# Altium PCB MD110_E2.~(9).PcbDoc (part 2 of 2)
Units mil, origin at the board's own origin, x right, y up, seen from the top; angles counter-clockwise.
Board outline 2320.51 x 1908 mil, 4 copper layers (Top Layer, Signal Layer 1, Signal Layer 2, Bottom Layer), stack 61.2 mil thick; 89 components, 32 nets, 187 pads, 40 vias.
Unrouted connection lines stored in the file: 7.

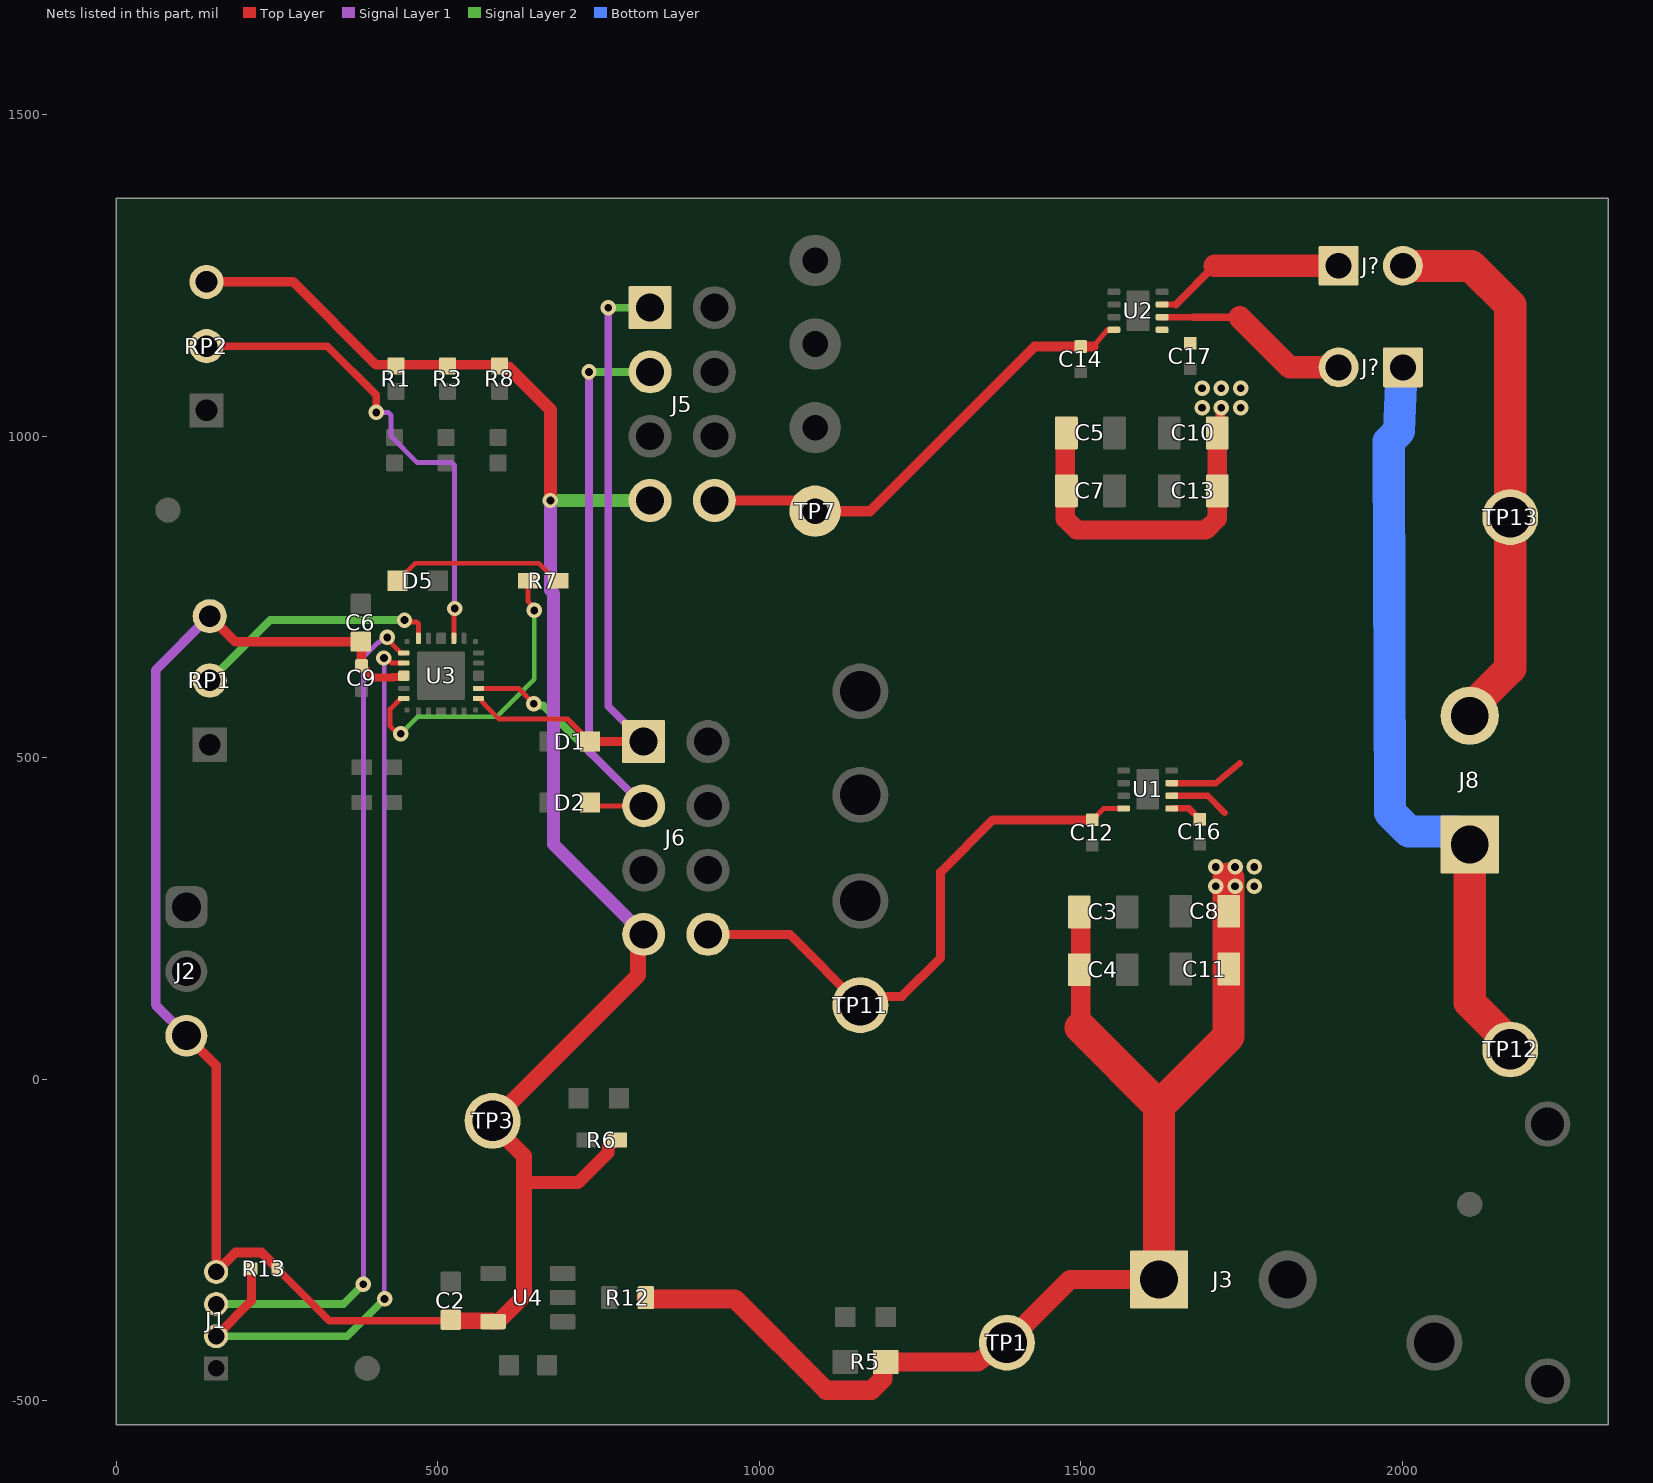
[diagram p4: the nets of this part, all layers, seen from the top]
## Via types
v1: diameter 24, hole 12, Top Layer to Bottom Layer, tented both sides, 36 vias
v2: diameter 19.68, hole 7.87, Top Layer to Bottom Layer, tented both sides, 4 vias

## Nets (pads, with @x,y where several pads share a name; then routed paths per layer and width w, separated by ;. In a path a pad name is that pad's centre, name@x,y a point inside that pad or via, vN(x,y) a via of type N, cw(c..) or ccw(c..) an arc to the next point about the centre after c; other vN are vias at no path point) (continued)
NetD5_2: D5.2 R7.2 | length 273.3
  Top Layer w7.5: D5.2@437.01,775 464.38,802.37 656.63,802.37 675.25,783.75 675.25,783.06 683.31,775 R7.2@687.24,775
OUT1: J8.1 J?.1@2001,1107 TP12.1 U1.2 | length 1273.9
  Top Layer w10: U1.2@1641.4,440.65 1697.35,440.65 1723.61,414.39
  Top Layer w50: J8.1@2105,365 2105,119.01 2168,56.01 TP12.1@2168,46
  Bottom Layer w50: J?.1@1999,1099 1995.09,1008.09 1979,992 1981,414.57 2010.29,385.28 2084.72,385.28 J8.1@2105,365
OUT1_B: J?.2@1901,1107 U2.2 | length 306.9
  Top Layer w10: U2.2@1626.4,1185.16 1675,1185
  Top Layer w12: 1675,1185 1747,1185
  Top Layer w35: 1747,1185 1825,1107 J?.2@1901,1107
OUT2: J8.2 J?.2@2001,1265 TP13.1 U1.3 | length 974.1
  Top Layer w10: U1.3@1641.4,460.34 1710.17,460.34 1747,491
  Top Layer w50: J?.2@2001,1265 2107,1265 2168,1204 TP13.1@2168,874 2168,638.97 2105,575.97 J8.2@2105,565
OUT2_B: J?.1@1901,1265 U2.3 | length 299.6
  Top Layer w10: U2.3@1626.4,1204.84 1647.68,1204.69
  Top Layer w12: 1647.68,1204.69 1708,1265
  Top Layer w35: 1708,1265 J?.1@1901,1265
PWM1: D1.2 J5.1 J6.1 U3.13 | length 1050.3
  Top Layer w7.5: U3.13@563.07,591.97 567.99,591.97 568.18,591.78 568.18,587.38 573.71,581.85 573.71,581.33 595.04,560 701.5,560
  Top Layer w8: 701.5,560 D1.2@736.5,525
  Top Layer w14: D1.2@736.5,525 J6.1@820,525
  Signal Layer 1 w12: v1(765,1200) 765,580 J6.1@820,525
  Signal Layer 2 w12: v1(765,1200) J5.1@830,1200
PWM2: D2.2 J5.3 J6.3 U3.14 | length 1223.4
  Top Layer w7.5: U3.14@563.07,607.72 625.28,607.72 v1(649,584)
  Top Layer w8: D2.2@736.5,430 741.5,425 J6.3@820,425
  Signal Layer 1 w12: v1(735,1100) 735,510 J6.3@820,425
  Signal Layer 2 w12: v1(649,584) 651.94,581.06 663.94,581.06 J6.3@820,425 ; v1(735,1100) J5.3@830,1100
SBWTCK: J1.3 U3.1 | length 1304.7
  Top Layer w7.5: v1(421,687) 421,683.84 442.01,662.83 U3.1@446.93,662.83
  Signal Layer 1 w7.5: v1(384,-319) 384,656.41 406.21,678.62 408.16,678.62 416.54,687 v1(421,687)
  Signal Layer 2 w12: J1.3@155,-350 353,-350 v1(384,-319)
SBWTDIO: J1.2 R13.2 U3.2 | length 1445.4
  Top Layer w7.5: v1(416,655) 420.1,655 428.02,647.09 U3.2@446.93,647.09
  Top Layer w14: J1.2@155,-400 209.82,-345.18 R13.2@209.82,-295
  Signal Layer 1 w7.5: v1(416,655) 416.5,654.5 416.5,-341.5 v1(417,-342)
  Signal Layer 2 w12: J1.2@155,-400 359,-400 v1(417,-342)
SPD_REF_1: RP2.2 U3.20 | length 767.6
  Top Layer w7.5: U3.20@524.69,685.47 524.87,685.66 524.87,730.87 v1(526,732)
  Top Layer w12: RP2.2@140,1140 328,1140 404,1064 v1(404,1037)
  Signal Layer 1 w7.5: v1(404,1037) 422.61,1037 427,1032.61 427,999.59 467.59,959 521.61,959 526,954.61 v1(526,732)
SPD_REF_2: RP1.2 U3.23 | length 388.8
  Top Layer w7.5: v1(448,714) 451.16,710.84 467.29,710.84 469.57,708.57 U3.23@469.57,685.47
  Signal Layer 2 w12: RP1.2@145,620 239,714 v1(448,714)
STATUS: R7.1 U3.5 | length 476.4
  Top Layer w7.5: v1(442,537) 437.54,537 425.54,549 425.54,575.5 442.01,591.97 U3.5@446.93,591.97 ; R7.1@640,775 640,743.34 649.87,733.46 v1(649.87,729)
  Signal Layer 2 w7.5: v1(442,537) 468.62,563.62 591.69,563.62 649.87,621.81 v1(649.87,729)
VCC: C2.2 C6.2 C9.2 J1.4 J2.3 J5.7 J6.7 R1.2 R3.2 R6.1 R8.2 R13.1 RP1.3 RP2.3 TP3.1 U3.3 U4.5 | length 4508
  Top Layer w12: R13.1@250.18,-295.49 253.53,-298.84 254.02,-298.84 331.14,-375.96 C2.2@521.44,-375.96 ; C9.2@385.06,639.38 399.78,624.65 429.24,624.65 430.12,625.53 445.06,625.53 U3.3@446.93,627.4
  Top Layer w15: J2.3@108.76,67.48 155,21.24 J1.4@155,-300 185.22,-269.78 225.45,-269.78 250.18,-294.51 R13.1@250.18,-295 R13.1@250.18,-295.49 ; RP2.3@140,1240 275,1240 404,1111 R8.2@592,1111 ; RP1.3@145,720 184.53,680.47 C6.2@380,680.47 380.61,679.86 380.61,643.83 C9.2@381.22,643.22
  Top Layer w20: R8.2@595,1110 598.69,1106.31 609.86,1106.31 675,1041.17 v1(675,900) ; 634,-161.17 718.05,-161.17 765,-114.21 765,-104.68 774.68,-95 R6.1@778.62,-95
  Top Layer w25: C2.2@521.44,-375.96 584.43,-375.96 U4.5@585.87,-377.4 593.74,-377.4 634,-337.14 634,-161.17 634,-119.94 585,-70.94 TP3.1@585,-65 811.54,161.54 811.54,216.54 J6.7@820,225
  Signal Layer 1 w15: J2.3@108.76,67.48 60.91,115.33 60.91,635.91 RP1.3@145,720
  Signal Layer 1 w20: v1(675,900) 675,760.44 679.75,755.69 679.75,365.25 J6.7@820,225
  Signal Layer 2 w20: v1(675,900) J5.7@830,900
VCC_DRV: C12.2 J6.8 TP11.1 U1.8 | length 896.8
  Top Layer w8: C12.2@1518,403.18 1535.79,420.97 U1.8@1566.6,420.97
  Top Layer w14: J6.8@920,225 1047,225 TP11.1@1157,115 1170.5,128.5 1221.5,128.5 1282,189 1282,322 1363.18,403.18 C12.2@1518,403.18
VCC_DRV_B: C14.2 J5.8 TP7.1 U2.8 | length 736.7
  Top Layer w8: 1519.33,1139.45 U2.8@1541.76,1165.47
  Top Layer w16: J5.8@930,900 1056.47,900 1073.19,883.28 TP7.1@1086.72,883.28 1172.04,883.28 1428.2,1139.45 C14.2@1500,1139.45 1519.33,1139.45
VM: C3.1 C4.1 C5.1 C7.1 C8.1 C10.1 C11.1 C13.1 C16.2 C17.2 J3.1 R5.1 R12.1 TP1.1 U1.1 U2.1 | length 2602.6
  Top Layer w10: U1.1@1641.4,420.97 1668.4,420.97 C16.2@1685,404.37 1685,403.16 1689.84,398.32 1689.84,399.53 C16.2@1685.61,403.76
  Top Layer w15: C10.1@1712.4,1005 1716.88,1009.47 1716.88,1042.62 v1(1718.6,1044.35)
  Top Layer w30: R12.1@823.54,-340 825.54,-342 962,-342 1104,-484 1174.24,-484 1191.81,-466.43 1191.81,-443.7 1195.51,-440 R5.1@1196.5,-440 1339.58,-440 TP1.1@1385,-410 ; TP1.1@1369.58,-410 TP1.1@1385,-410 ; C5.1@1477.6,1005 1476,1003.4 1476,871.57 1493.57,854 1694.83,854 1712.4,871.57 C13.1@1712.4,915 C10.1@1712.4,1005 ; C3.1@1497.6,260 1500,257.6 1500,80 ; J3.1@1621.81,-311.89 1483.11,-311.89 TP1.1@1385,-410
  Top Layer w50: 1500,80 1621.81,-41.81 ; J3.1@1621.81,-311.89 1621.81,-41.81 ; 1730,312 1730,66.38 1621.81,-41.81
  other v1: 1710,300 1740,300 1770,300 1710,330 1740,330 1770,330 1688.6,1044.35 1748.6,1044.35 1688.6,1074.35 1718.6,1074.35 1748.6,1074.35
pads on no net: FID1.1 FID2.1 FID3.1 H1.0 H2.0 H3.0 H4.0 SH-J1.0 SH-J2.0 SH-J3.0 SH-J4.0 SH-J5.0 SH-J6.0 SH-J7.0 SH-J8.0 SH-J9.0 SH-J10.0 SH-J11.0 U3. U3.6 U3.7 U3.8 U3.9 U3.10 U3.12 U3.18 U3.19 U3.21 U3.22 U3.24 U4.2

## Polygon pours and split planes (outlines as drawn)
VM on Top Layer "TOP_LAYER_VM_P029" (solid, remove dead copper, pour order 29): 1610.6,1160.35 1610.6,1171 1675.94,1171 1768.6,1078.35 1768.6,1028.35 1682.6,1028.35 1673.6,1037.35 1673.6,1126.35 1644.6,1126.35
VM on Top Layer "TOP_LAYER_VM_P024" (solid, remove dead copper, pour order 24): 1632,416 1632,429 1695,429 1790,334 1790,284 1704,284 1695,293 1695,382 1682,382 1648,416
OUT2 on Top Layer "TOP_LAYER_OUT2_P022" (solid, pour order 22): 2302.5,450.5 2302.5,717.1 1956,717.1 1666.75,450.5
OUT1 on Top Layer "TOP_LAYER_OUT1_P021" (solid, pour order 21): 1680.36,448.5 2304,448.5 2304,187.5 1968.91,187.5
GND on Top Layer "TOP_LAYER_GND_P056" (solid, remove dead copper, pour order 30): 0,1370 2320.51,1370 2320.51,-620 0,-620
VM on Bottom Layer "BOTTOM_LAYER_VM_P026" (solid, remove dead copper, pour order 26): 1690,280 1790,280 1790,1080 1780,1090 1670,1090 1670,1030 1690,1010
GND on Bottom Layer "BOTTOM_LAYER_GND_P031" (solid, remove dead copper, pour order 31): 0,-538 2320.51,-538 2320.51,1370 0,1370
GND on Signal Layer 1 "TOP_LAYER_GND_P056" (solid, remove dead copper, pour order 27): 5.76,1379.32 2326.27,1379.32 2326.27,-610.68 5.76,-610.68
GND on Signal Layer 2 "TOP_LAYER_GND_P056" (solid, remove dead copper, pour order 28): 0,1370 2320.51,1370 2320.51,-620 0,-620

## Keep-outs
Keep-Out Layer:
  text ".Layer_Name" at 573,-2319.49 h25

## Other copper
Top Layer:
  text ".Layer_Name" at 573,-2319.49 h25
Bottom Layer:
  text ".Layer_Name" at 573,-2319.49 h25

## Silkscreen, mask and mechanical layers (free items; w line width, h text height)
Top Overlay:
  circle w10: c425,710 r5
  lines w8: 23.97,-495 325,-495 325,-260 23.97,-260 23.97,-495 ; 40,-145 445,-145 445,375 40,375 40,-145 ; 40.2,-144.55 445.2,-144.55 445.2,15.45 40.2,15.45 40.2,-144.55 ; 390.95,897.85 640.95,897.85 640.95,1177.85 390.95,1177.85 390.95,897.85 ; 480,-485 855,-485 855,-224.06 480,-224.06 480,-485 ; 748.99,790 2080,790 2080,1340 748.99,1340 748.99,790
  lines w10: 1480,335.31 1480,525.05 1708.27,523.61 1708.72,334.56 1480,335.31
  lines w15: 907.34,-180 1460,-180 1460,-20 907.34,-20 907.34,-180
  text "IN1/EN PWM" at 244.21,1313.67 h65 r270
  text "OUT2_B" at 1678,1287.31 h45
  text "OUT2" at 2087,1283.34 h45
  text "Parallel / DRV8218" at 752.21,1260.58 h48
  text "IN1/EN" at 1168.72,1255.67 h55
  text "EVM ID / Resistors" at 388.16,1178.81 h48
  text "IN2/PH" at 1168.72,1130.67 h55
  text "OUT1_B" at 1679,1130.31 h45
  text "OUT1" at 2087,1126.52 h45
  text "ID1" at 407.25,1021.94 h40
  text "ID2" at 490.24,1021.94 h40
  text "ID3" at 571.12,1021.94 h40
  text "MODE" at 1168.72,995.67 h55
  text "VCC" at 1168.72,865.65 h55
  text "MCU Status" at 417.62,815.8 h60
  text "IN2/PH PWM" at 259.21,793.67 h65 r270
  text "OUT2" at 2078.94,732.4 h80
  text "IN1/EN" at 1239,579.21 h65
  text "DRV8218DSG" at 1429.12,535.8 h60
  text "IN2/PH" at 1239,421.21 h65
  text "MODE" at 1239,255.21 h65
  text "GND" at 176.76,253.28 h60
  text "MODE" at 178.76,141.88 h80
  text "OUT1" at 2077.98,123.4 h80
  text "VCC" at 1239,93.18 h65
  text "VCC" at 173.51,48.25 h60
  text "VCC" at 516.33,19.36 h80
  text "VCC LED" at 703.56,5.77 h60
  text "1.8V - 11V" at 1615,5.05 h50
  text "VM" at 1548.94,-65.6 h80
  text "GND" at 1743.6,-69.59 h80
  text "GND = PWM / VCC = PH/EN / Hi-Z  = ½ bridge" at 55,-146.12 h60
  text "Max VCC: 3.3V" at 487.24,-174.2 h60
  text "DRV8218EVM" at 910,-179.63 h115
  text "3.3V LDO" at 478.72,-220.94 h48
  text "'.PRJ_Number'.PCB_Rev" at 903.48,-248.02 h72.83
  text "Programming" at 23.72,-259.89 h48
  text "VM" at 1333.94,-325.6 h80
  text "GND" at 1979,-325.6 h80
  text "VM LED" at 1034.93,-334.2 h60
  text "0Ω" at 755.31,-427.42 h70
  text ".Layer_Name" at 573,-2319.49 h25
Bottom Overlay:
  text ".Layer_Name" at 573,-2319.49 h25
Top Paste:
  text ".Layer_Name" at 573,-2319.49 h25
Bottom Paste:
  text ".Layer_Name" at 573,-2319.49 h25
Top Solder:
  text ".Layer_Name" at 573,-2319.49 h25
  text ".Layer_Name" at 573,-2319.49 h25
Bottom Solder:
  text ".Layer_Name" at 573,-2319.49 h25
Drill Guide:
  text ".Layer_Name" at 573,-2319.49 h25
M1 Board Outline:
  the board outline again, w10
  text ".Layer_Name" at 573,-2319.49 h25
M2 Board Dimensions:
  rectangle: -4,-1736 121,-1611
  rectangle: 121,-1861 496,-1736
  lines w7: -4,-1736 996,-1736 ; 121,-1861 121,-1611 ; 246,-1861 246,-1611 ; 496,-1861 496,-1611 ; 746,-1861 746,-1611 ; -4,-1861 996,-1861 996,-1611 -4,-1611 -4,-1861
  text ".Layer_Name" at 573,-2319.49 h25
M3 3D STEP Top:
  text ".Layer_Name" at 573,-2319.49 h25
M4 3D STEP Bottom:
  text ".Layer_Name" at 573,-2319.49 h25
M5 Assembly Top:
  lines w10: -296,-2391.17 6304,-2391.17 ; -296,-2187.83 6306,-2187.83 ; -296,-1984.5 -296,-2594.5 3709,-2594.5 6306,-2594.5 6306,-1984.5 -295.5,-1984.5 -295.5,-2594.5 1280,-2594.5 ; 2169,-2594.5 2169,-1984.5 ; 3436,-2187.83 3436,-1984.5 ; 4276,-2187.83 4276,-1984.5 ; 4898,-2601 4898,-2398.17
  text "COMPONENTS MARKED 'DNP' SHOULD NOT BE POPULATED." at 1149.5,-1779.5 h25
  text "ASSEMBLY VARIANT:" at 1149,-1895 h25
  text ".VariantName" at 2185,-1895 h25
  text "PCB VIEWED FROM TOP SIDE" at -232.5,-2116.67 h25
  text "BOARD #:" at 2244,-2116.67 h25
  text ".PRJ_Number" at 2789.5,-2116.67 h25
  text "REV:" at 3634,-2116.67 h25
  text ".PCB_Rev" at 3925.5,-2116.67 h25
  text "SVN REV:" at 4472,-2116.67 h25
  text ".VersionControl_RevNumber" at 4978,-2116.67 h25
  text "TID #:" at 2244,-2320 h25
  text ".TID" at 2789.5,-2320 h25
  text "PLOT NAME =" at -232.5,-2525.34 h25
  text ".plot_File_Name" at 573,-2525.34 h25
  text "GENERATED    :" at 2246,-2525.34 h25
  text ".Print_Date" at 3115.5,-2525.34 h25
  text ".Print_Time" at 3844.5,-2525.34 h25
  text "TEXAS INSTRUMENTS" at 5109,-2525.34 h25
M6 Assembly Bottom:
  lines w10: -296.5,-2188.33 6305.5,-2188.33 ; -294.5,-2391.67 6305.5,-2391.67 ; 1111.5,-2601.5 1111.5,-2398.67 ; 1733.5,-2188.33 1733.5,-1985 ; 2573.5,-2188.33 2573.5,-1985 ; 3840.5,-2595 3840.5,-1985 ; 4729.5,-2595 6305,-2595 6305,-1985 -296.5,-1985 -296.5,-2595 2300.5,-2595 6305.5,-2595 6305.5,-1985
  text "COMPONENTS MARKED 'DNP' SHOULD NOT BE POPULATED." at 6098,-1779 h25
  text ".VariantName" at 5054,-1895 h25
  text "ASSEMBLY VARIANT:" at 6093,-1895 h25
  text ".VersionControl_RevNumber" at 1031.5,-2117.17 h25
  text "SVN REV:" at 1537.5,-2117.17 h25
  text ".PCB_Rev" at 2084,-2117.17 h25
  text "REV:" at 2375.5,-2117.17 h25
  text ".PRJ_Number" at 3220,-2117.17 h25
  text "BOARD #:" at 3765.5,-2117.17 h25
  text "PCB VIEWED FROM BOTTOM SIDE" at 6242,-2117.17 h25
  text ".TID" at 3220,-2320.5 h25
  text "TID #:" at 3765.5,-2320.5 h25
  text "TEXAS INSTRUMENTS" at 900.5,-2525.84 h25
  text ".Print_Time" at 2165,-2525.84 h25
  text ".Print_Date" at 2894,-2525.84 h25
  text "GENERATED    :" at 3763.5,-2525.84 h25
  text ".plot_File_Name" at 5436.5,-2525.84 h25
  text "PLOT NAME =" at 6242,-2525.84 h25
M9 Title Sheet:
  drawing of 57 lines, arcs and shapes, not listed
  text "1" at 735.84,6575.5 h25
  text "2" at 3231.5,6575.5 h25
  text "3" at 5720.84,6575.5 h25
  text "4" at 8227.51,6575.5 h25
  text "5" at 10726.5,6575.5 h25
  text "6" at 13231.5,6575.5 h25
  text "A" at -420.5,5432.5 h25
  text "A" at 14379.5,5432.5 h25
  text "B" at -420.5,3052.5 h25
  text "B" at 14379.5,3052.5 h25
  text "C" at -420.5,677.5 h25
  text "C" at 14379.5,677.5 h25
  text "PROJECT TITLE:" at 11339.5,-1183.5 h25
  text ".PRJ_Title" at 11389.5,-1316.83 h25
  text "DESIGNED FOR:" at 11339.5,-1484.5 h25
  text ".PRJ_Customer" at 11389.5,-1624.5 h25
  text "D" at -420.5,-1692.5 h25
  text "D" at 14379.5,-1692.5 h25
  text "FILE NAME:" at 11339.5,-1784.5 h25
  text ".PCB_File_Name_No_Path" at 11389.5,-1904.5 h25
  text "Texas Instruments (TI) and/or its licensors do not warrant the accuracy or completeness of this specification" at 6370,-2066.34 h25
  text "ENGINEER:" at 11339.5,-2074.5 h25
  text "LAYOUT BY:" at 12844.5,-2074.5 h25
  text "or any information contained therein. TI and/or its licensors do not warrant that this design will meet" at 6325.01,-2179 h25
  text ".PRJ_Engineer" at 11389.5,-2229.49 h25
  text ".PCB_Layout" at 12895,-2229.49 h25
  text "the specifications, will be suitable for your application or fit for any particular purpose, or will operate in" at 6325.01,-2291.67 h25
  text ".Layer_Name" at 573,-2319.49 h25
  text "ALTIUM DESIGNER VERSION:" at 12844.5,-2384.5 h25
  text "an implementation. TI and/or its licensors do not warrant that the design is production worthy. You should" at 6325.01,-2404.33 h25
  text "completely validate and test your design implementation to confirm the system functionality for your application." at 6370,-2517 h25
  text ".print_Scale" at 11389.5,-2517.83 h25
  text ".Application_BuildNumber" at 12895,-2517.83 h25
  text "1" at 735.84,-2724.5 h25
  text "2" at 3231.5,-2724.5 h25
  text "3" at 5720.84,-2724.5 h25
  text "4" at 8227.51,-2724.5 h25
  text "5" at 10726.5,-2724.5 h25
  text "6" at 13231.5,-2724.5 h25
M10 Fab Notes:
  drawing of 189 lines, arcs and shapes, not listed
  text "DESIGN INFORMATION" at 12378.02,4895.17 h25
  text "MIN. TRACK WIDTH:" at 11733.46,4763.05 h25
  text "8" at 12829.7,4763.05 h25
  text "MIL" at 12984.46,4763.05 h25
  text "MIN. CLEARANCE:" at 11733.46,4638.92 h25
  text "0.2" at 12769.7,4638.93 h25
  text "mm" at 12984.46,4638.92 h25
  text "MIN. VIA PAD SIZE:" at 11733.46,4514.8 h25
  text "24" at 12799.71,4514.8 h25
  text "MIL" at 12984.46,4514.8 h25
  text "0.05mm (2MIL)" at 12428.46,4384.9 h25
  text "MINIMUM ANNULAR RING" at 11404.23,4376.67 h25
  text "EXTERNAL" at 13136.46,4376.67 h25
  text "PER" at 11604.23,4266.55 h25
  text "IPC-D-275 CLASS 2 LEVEL C" at 11824.23,4266.54 h25
  text "MIL, HOLES" at 13312.46,4166.07 h25
  text "+/-" at 12920,4157.48 h25
  text "+/-" at 13774,4157.48 h25
  text "REGISTRATION TOLERANCES:" at 11404.23,4156.42 h25
  text "METAL" at 12604,4156.42 h25
  text "5" at 13180.2,4156.42 h25
  text "3" at 14013.2,4156.42 h25
  text "MIL" at 14129.46,4156.42 h25
  text "HOLE SIZE TOLERANCE (UNLESS OTHERWISE SPECIFIED):" at 11404.23,4058.1 h25
  text "+/-" at 13774,4055.23 h25
  text "3" at 14013.2,4054.17 h25
  text "MIL" at 14129.46,4054.17 h25
  text "MATERIAL:" at 11329.46,3916.52 h25
  text "FR-4 High Tg" at 12315.9,3788 h25
  text "X" at 12171.46,3780.01 h25
  text "FR-408" at 11750.46,3775.49 h25
  text "OTHER" at 13238.46,3775.49 h25
  text "62 MIL (1.6mm) +/-10%" at 12070.56,3632.46 h25
  text "X" at 11950.46,3630.01 h25
  text "THICKNESS:" at 11404.23,3624.24 h25
  text "OTHER" at 13355.46,3624.24 h25
  text "TOLERANCE:" at 11404.23,3485.92 h25
  text "X" at 12252.46,3485.92 h25
  text "ANSI IPC-6012 TYPE 3 CLASS 2" at 12430.48,3485.92 h25
  text "OTHER +/-" at 12430.46,3341.73 h25
  text "BOW & TWIST:" at 11404.23,3196.54 h25
  text "X" at 12252.46,3196.54 h25
  text "ANSI IPC-6012 TYPE 3 CLASS 2" at 12430.48,3196.54 h25
  text "OTHER +/-" at 12430.46,3049.85 h25
  text "DRILLING:" at 11329.46,2919.23 h25
  text "NC_DRILL FILES" at 13090.46,2814.04 h25
  text "REFERENCE:" at 11404.23,2810.1 h25
  text "X" at 12061.46,2810.01 h25
  text "AS SHOWN" at 12239.46,2810.1 h25
  text "X" at 12962.46,2810.1 h25
  text "OTHER" at 13388.46,2667.85 h25
  text "PTH COPPER THICKNESS:" at 11403.91,2664.32 h25
  text "X" at 12543.14,2664.32 h25
  text "20-30 um" at 12671.14,2664.32 h25
  text "BOARD FINISH:" at 11329.46,2516.73 h25
  text "SILKSCREEN:" at 11484.68,2406.6 h25
  text "X" at 12442.46,2406.6 h25
  text "TOP" at 12559.46,2406.6 h25
  text "X" at 12952.46,2406.6 h25
  text "BOTTOM" at 13070.46,2406.6 h25
  text "SILKSCREEN COLOR:" at 11484.68,2251.41 h25
  text "X" at 12441.46,2251.41 h25
  text "WHITE" at 12559.46,2251.41 h25
  text "OTHER" at 13070.46,2251.41 h25
  text "X" at 12572.46,2107.96 h25
  text "GREEN" at 12690.46,2107.96 h25
  text "OTHER" at 13308.46,2107.96 h25
  text "SOLDER RESIST COLOR:" at 11484.68,2101.1 h25
  text "X" at 12572.46,1953.71 h25
  text "MATTE" at 12690.46,1953.71 h25
  text "SEMI-GLOSS" at 13308,1953.07 h25
  text "IMMERSION GOLD (ENIG)" at 12390.46,1780.94 h25
  text "ENEPIG" at 13728,1773.72 h25
  text "SURFACE FINISH:" at 11329.46,1772.72 h25
  text "X" at 12212.46,1772.72 h25
  text "IMM. TIN/SILVER OR EQUIV" at 11659,1635.4 h25
  text "OTHER" at 13090.46,1631.47 h25
  text "ARRAY/PANEL:" at 11329.46,1476.09 h25
  text "CUT AND TRIM PER M1 BOARD OUTLINE" at 12390.46,1467.87 h25
  text "N.C. ROUTE" at 12390.46,1331.9 h25
  text "X" at 13078.46,1331.9 h25
  text "V. SCORE" at 13256.46,1331.9 h25
  text "CERTIFICATION:" at 11329.46,1202.77 h25
  text "MATERIALS AND WORKMANSHIP FOR ALL PCBS" at 12054.46,1202.77 h25
  text "TO MEET OR EXCEED THE REQUIREMENTS OF:" at 12054.46,1108.71 h25
  text "X" at 11691.97,980.08 h25
  text "ANSI IPC-A-600F CLASS ->" at 11819.96,980.08 h25
  text "X" at 13467.97,980.08 h25
  text "2" at 13577.96,980.08 h25
  text "1" at 13262.96,978.58 h25
  text "3" at 13931.96,978.58 h25
  text "X" at 12503.97,832.39 h25
  text "RoHS" at 12631.96,832.39 h25
  text "OTHER" at 13276.36,832.39 h25
  text "PER ORDER" at 13673.42,832.39 h25
  text "ALL BOARDS MUST MEET OR EXCEED UL94-V0 REQUIREMENTS." at 11357,678.57 h25
  text "PCB MUST BEAR THE UL94V-0 UL REGISTERED MATERIAL ID NUMBER" at 11357,562.5 h25
  text "ADDITIONAL REQUIREMENTS:" at 11329.46,393.08 h25
  text "MICROSECTION:" at 11404.23,285.95 h25
  text "YES" at 12309.96,285.95 h25
  text "REQUIRED" at 13171.46,141.62 h25
  text "BARE BOARD ELEC. TEST:" at 11404.23,138.76 h25
  text "NONE" at 12709.96,138.76 h25
  text "X" at 13053.46,138.76 h25
  text "PER ORDER" at 13763.46,138.76 h25
  text "XX MIL VIAS REQUIRE NON-CONDUCTIVE FILL AND PLANARIZE" at 11572.38,-66.18 h25
  text "XX MIL VIAS REQUIRE CONDUCTIVE FILL AND PLANARIZE" at 11580.38,-170.16 h25
  text "OUTER XX MIL TRACES REQUIRE 50 OHM SINGLE-ENDED IMPEDANCE" at 11579.39,-333.54 h25
  text "LAYER 2 & 3 (INNER LAYERS) XX MIL WIDE, XX MIL SPACE / TRACES REQUIRE 100 OHM DIFFERENTIAL IMPEDANCE" at 11571.39,-569.26 h25
  text ".Layer_Name" at 573,-2319.49 h25
M11 Gerber Information:
  lines w10: -296,-2391.17 6304,-2391.17 ; -296,-2187.83 6306,-2187.83 ; -296,-1984.5 -296,-2594.5 3709,-2594.5 6306,-2594.5 6306,-1984.5 -295.5,-1984.5 -295.5,-2594.5 1280,-2594.5 ; 2169,-2594.5 2169,-1984.5 ; 3436,-2187.83 3436,-1984.5 ; 4276,-2187.83 4276,-1984.5 ; 4898,-2601 4898,-2398.17
  text "ALL ARTWORK VIEWED FROM TOP SIDE" at -232.5,-2116.67 h25
  text "BOARD #:" at 2244,-2116.67 h25
  text ".PRJ_Number" at 2789.5,-2116.67 h25
  text "REV:" at 3634,-2116.67 h25
  text ".PCB_Rev" at 3925.5,-2116.67 h25
  text "SVN REV:" at 4472,-2116.67 h25
  text ".VersionControl_RevNumber" at 4978,-2116.67 h25
  text "LAYER NAME =" at -232.5,-2319.49 h25
  text "TID #:" at 2244,-2320 h25
  text ".TID" at 2789.5,-2320 h25
  text "PLOT NAME =" at -232.5,-2525.34 h25
  text ".plot_File_Name" at 573,-2525.34 h25
  text "GENERATED    :" at 2246,-2525.34 h25
  text ".Print_Date" at 3115.5,-2525.34 h25
  text ".Print_Time" at 3844.5,-2525.34 h25
  text "TEXAS INSTRUMENTS" at 5109,-2525.34 h25
M12 Stackup:
  drawing of 306 lines, arcs and shapes, not listed
  text "Layer" at 9167.67,528.5 h25
  text "Name" at 9350.13,528.5 h25
  text "Material" at 9753.36,528.5 h25
  text "Thickness" at 10123.26,528.5 h25
  text "Constant" at 10405.69,528.5 h25
  text "Board Layer Stack" at 10654.8,528.5 h25
  text "Top Overlay" at 9350.13,478.5 h25
  text "Top Solder" at 9350.13,428.5 h25
  text "Solder Resist" at 9753.36,428.5 h25
  text "0.40mil" at 10123.26,428.5 h25
  text "3.5" at 10405.69,428.5 h25
  text "1" at 9167.67,378.5 h25
  text "Top Layer" at 9350.13,378.5 h25
  text "2.80mil" at 10123.26,378.5 h25
  text "Dielectric 1" at 9350.13,328.5 h25
  text "FR4 370" at 9753.36,328.5 h25
  text "11.40mil" at 10123.26,328.5 h25
  text "4.2" at 10405.69,328.5 h25
  text "2" at 9167.67,278.5 h25
  text "Signal Layer 1" at 9350.13,278.5 h25
  text "1.40mil" at 10123.26,278.5 h25
  text "Dielectric 2" at 9350.13,228.5 h25
  text "FR4 370" at 9753.36,228.5 h25
  text "30.00mil" at 10123.26,228.5 h25
  text "4.2" at 10405.69,228.5 h25
  text "3" at 9167.67,178.5 h25
  text "Signal Layer 2" at 9350.13,178.5 h25
  text "1.40mil" at 10123.26,178.5 h25
  text "Dielectric 3" at 9350.13,128.5 h25
  text "FR4 370" at 9753.36,128.5 h25
  text "11.40mil" at 10123.26,128.5 h25
  text "4.2" at 10405.69,128.5 h25
  text "4" at 9167.67,78.5 h25
  text "Bottom Layer" at 9350.13,78.5 h25
  text "2.80mil" at 10123.26,78.5 h25
  text "Bottom Solder" at 9350.13,28.5 h25
  text "Solder Resist" at 9753.36,28.5 h25
  text "0.40mil" at 10123.26,28.5 h25
  text "3.5" at 10405.69,28.5 h25
  text "Bottom Overlay" at 9350.13,-21.5 h25
  text ".Layer_Name" at 573,-2319.49 h25
M13 Component Bodies Top:
  text ".Layer_Name" at 573,-2319.49 h25
M14 Component Bodies Bottom:
  text ".Layer_Name" at 573,-2319.49 h25
M15 Courtyards Top:
  text ".Layer_Name" at 573,-2319.49 h25
M16 Courtyards Bottom:
  text ".Layer_Name" at 573,-2319.49 h25
Drill Drawing:
  circle w10: c9770.85,-216.34 r6.9
  circle w10: c9770.85,-216.34 r11.5
  circle w10: c9770.85,-630.29 r11.5
  lines w10: 9759.36,-739.53 9765.1,-739.53 9765.1,-745.28 9776.6,-745.28 9776.6,-739.53 9782.35,-739.53 9782.35,-728.03 9776.6,-728.03 9776.6,-722.28 9765.1,-722.28 9765.1,-728.03 9759.36,-728.03 9759.36,-739.53 ; 9759.36,-693.54 9759.36,-687.79 9765.1,-682.04 9759.36,-676.29 9759.36,-670.54 9765.1,-670.54 9770.85,-676.29 9776.6,-670.54 9782.35,-670.54 9782.35,-676.29 9776.6,-682.04 9782.35,-687.79 9782.35,-693.54 9776.6,-693.54 9770.85,-687.79 9765.1,-693.54 9759.36,-693.54 ; 9759.36,-567.05 9782.35,-567.05 9770.85,-590.05 9759.36,-567.05 ; 9759.36,-538.31 9782.35,-538.31 9782.35,-515.31 9759.36,-515.31 9759.36,-538.31 ; 9759.36,-486.56 9782.35,-486.56 9782.35,-463.56 9759.36,-463.56 9759.36,-486.56 ; 9759.36,-429.07 9765.1,-429.07 9770.85,-434.82 9776.6,-429.07 9782.35,-429.07 9776.6,-423.32 9782.35,-417.57 9776.6,-417.57 9770.85,-411.82 9765.1,-417.57 9759.36,-417.57 9765.1,-423.32 9759.36,-429.07 ; 9759.36,-383.07 9770.85,-377.32 9782.35,-383.07 9776.6,-371.57 9782.35,-360.08 9770.85,-365.83 9759.36,-360.08 9765.1,-371.57 9759.36,-383.07 ; 9759.36,-325.58 9765.1,-325.58 9770.85,-331.33 9776.6,-325.58 9782.35,-325.58 9776.6,-319.83 9782.35,-314.08 9776.6,-314.08 9770.85,-308.33 9765.1,-314.08 9759.36,-314.08 9765.1,-319.83 9759.36,-325.58 ; 9759.36,-268.09 9770.85,-279.59 9782.35,-268.09 9770.85,-256.59 9759.36,-268.09 ; 9763.95,-481.96 9777.75,-481.96 9777.75,-468.16 9763.95,-468.16 9763.95,-481.96 ; 9763.95,-323.28 9767.4,-323.28 9770.85,-326.73 9774.3,-323.28 9777.75,-323.28 9774.3,-319.83 9777.75,-316.38 9774.3,-316.38 9770.85,-312.93 9767.4,-316.38 9763.95,-316.38 9767.4,-319.83 9763.95,-323.28
  lines w12: 9736.68,-760.8 11081.08,-760.8 ; 9736.68,-191.62 11081.08,-191.62 ; 9877.24,-812.55 9877.24,-139.88 ; 10015.35,-812.55 10015.35,-139.88 ; 10280.12,-812.55 10280.12,-139.88 ; 10387.93,-812.55 10387.93,-139.88 ; 10543.98,-812.55 10543.98,-139.88 ; 10845.46,-812.55 10845.46,-139.88 ; 9736.68,-812.55 11081.08,-812.55 11081.08,-139.88 9736.68,-139.88 9736.68,-812.55
  text "Symbol" at 9767.73,-176.1 h30
  text "Quantity" at 9892.76,-176.1 h30
  text "Finished Hole Size" at 10030.87,-176.1 h30
  text "Plated" at 10295.65,-176.1 h30
  text "Hole Type" at 10403.45,-176.1 h30
  text "Drill Layer Pair" at 10559.51,-176.1 h30
  text "Hole Tolerance" at 10860.99,-176.1 h30
  text "4" at 9892.76,-227.84 h25
  text "7.87mil (0.200mm)" at 10030.87,-227.84 h25
  text "PTH" at 10295.65,-227.84 h25
  text "Round" at 10403.45,-227.84 h25
  text "Top Layer - Bottom Layer" at 10559.51,-227.84 h25
  text "36" at 9892.76,-279.59 h25
  text "12.00mil (0.305mm)" at 10030.87,-279.59 h25
  text "PTH" at 10295.65,-279.59 h25
  text "Round" at 10403.45,-279.59 h25
  text "Top Layer - Bottom Layer" at 10559.51,-279.59 h25
  text "4" at 9892.76,-331.33 h25
  text "25.59mil (0.650mm)" at 10030.87,-331.33 h25
  text "PTH" at 10295.65,-331.33 h25
  text "Round" at 10403.45,-331.33 h25
  text "Top Layer - Bottom Layer" at 10559.51,-331.33 h25
  text "6" at 9892.76,-383.07 h25
  text "33.47mil (0.850mm)" at 10030.87,-383.07 h25
  text "PTH" at 10295.65,-383.07 h25
  text "Round" at 10403.45,-383.07 h25
  text "Top Layer - Bottom Layer" at 10559.51,-383.07 h25
  text "4" at 9892.76,-434.82 h25
  text "40.00mil (1.016mm)" at 10030.87,-434.82 h25
  text "PTH" at 10295.65,-434.82 h25
  text "Round" at 10403.45,-434.82 h25
  text "Top Layer - Bottom Layer" at 10559.51,-434.82 h25
  text "4" at 9892.76,-486.56 h25
  text "40.16mil (1.020mm)" at 10030.87,-486.56 h25
  text "PTH" at 10295.65,-486.56 h25
  text "Round" at 10403.45,-486.56 h25
  text "Top Layer - Bottom Layer" at 10559.51,-486.56 h25
  text "16" at 9892.76,-538.31 h25
  text "43.31mil (1.100mm)" at 10030.87,-538.31 h25
  text "PTH" at 10295.65,-538.31 h25
  text "Round" at 10403.45,-538.31 h25
  text "Top Layer - Bottom Layer" at 10559.51,-538.31 h25
  text "3" at 9892.76,-590.05 h25
  text "45.28mil (1.150mm)" at 10030.87,-590.05 h25
  text "PTH" at 10295.65,-590.05 h25
  text "Round" at 10403.45,-590.05 h25
  text "Top Layer - Bottom Layer" at 10559.51,-590.05 h25
  text "2" at 9892.76,-641.79 h25
  text "51.18mil (1.300mm)" at 10030.87,-641.79 h25
  text "PTH" at 10295.65,-641.79 h25
  text "Round" at 10403.45,-641.79 h25
  text "Top Layer - Bottom Layer" at 10559.51,-641.79 h25
  text "4" at 9892.76,-693.54 h25
  text "59.06mil (1.500mm)" at 10030.87,-693.54 h25
  text "PTH" at 10295.65,-693.54 h25
  text "Round" at 10403.45,-693.54 h25
  text "Top Layer - Bottom Layer" at 10559.51,-693.54 h25
  text "9" at 9892.76,-745.28 h25
  text "63.00mil (1.600mm)" at 10030.87,-745.28 h25
  text "PTH" at 10295.65,-745.28 h25
  text "Round" at 10403.45,-745.28 h25
  text "Top Layer - Bottom Layer" at 10559.51,-745.28 h25
  text "92 Total" at 9892.76,-797.03 h25
  text ".Layer_Name" at 573,-2319.49 h25
Mechanical 17:
  text ".Layer_Name" at 573,-2319.49 h25
Mechanical 18:
  text ".Layer_Name" at 573,-2319.49 h25
Mechanical 19:
  text ".Layer_Name" at 573,-2319.49 h25

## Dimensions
0,-538 to 2320.51,-538 on M1 Board Outline
0,1370 to 0,-538 on M2 Board Dimensions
